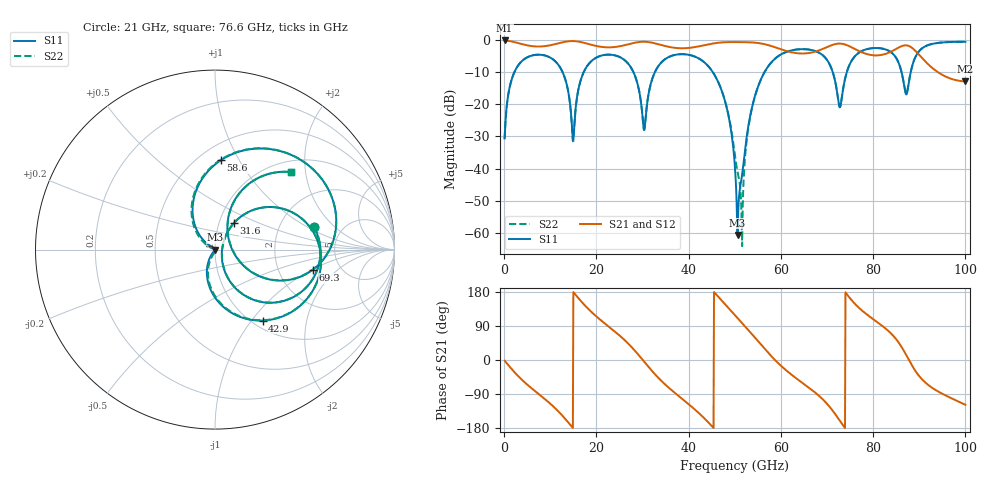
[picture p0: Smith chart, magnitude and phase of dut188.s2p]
! Touchstone file exported from HFSS 2026.1.0
!  File:  C:/ffzhzh/LocalFiles/Ansys_Project_Files/temp_test_TSV_RDL_188_1783478084_46308.aedt
!  Generated:  10:45:06 AM Jul  8, 2026
!  Design:  TSV_RDL
!  Project:  temp_test_TSV_RDL_188_1783478084_46308
! Variables:
!  h_bsmrdl = 2.62um
!  h_ox = 20um
!  h_rdl = 5um
!  h_sub = 55.96um
!  h_tmrdl = 3.07um
!  h_tsv = 55.96um
!  h_via = 3um
!  l_bsmrdl = 450.23um
!  l_sub = 4225.62um
!  l_tmrdl = 588.59um
!  m_sub = 200um
!  pitch = 55.14um
!  r_tsv = 11.97um
!  s_tmrdl = 10um
!  w_bsmrdl = 13.92um
!  w_sub = 500um
!  w_tmrdl = 26.27um
!  x_tsv_center1 = 601.725um
!  x_tsv_center2 = 1065.875um
!  x_tsv_center3 = 1680.735um
!  x_tsv_center4 = 2144.885um
!  x_tsv_center5 = 2759.745um
!  x_tsv_center6 = 3223.895um
# GHz S MA R 50.000000
! Terminal data exported
! Port[1] = TM_RDL1_1_T1
! Port[2] = TM_RDL5_1_T1
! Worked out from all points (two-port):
!   1000 points, 100 MHz to 100 GHz, reference 50 ohm
!   highest |S21| = -0.21 dB at 100 MHz (marker M1); lowest = -12.9 dB at 100 GHz (marker M2)
!   |S21| within 3 dB of the highest: start of sweep to 60.56 GHz; 68.43 GHz to 76.52 GHz (8.091 GHz wide, 11.2 % of centre) (the widest 2 of 3)
!   lowest |S11| = -60.6 dB at 50.6 GHz (marker M3), VSWR 1.00, Z = 50.1 - j0.0311 ohm
!   |S11| at or under -10 dB: 12.65 GHz to 17.27 GHz (4.615 GHz wide, 30.9 % of centre); 28.01 GHz to 32.7 GHz (4.686 GHz wide, 15.4 % of centre); 45.21 GHz to 56.47 GHz (11.26 GHz wide, 22.1 % of centre) (the widest 3 of 6)
!   |S22| runs from -64.1 to -0.6 dB; largest |S21 - S12| = 1.8e-14
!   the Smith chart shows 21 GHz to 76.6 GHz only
!   S11 on the Smith chart (normalised r, x): 21 GHz: 3.15, +1.15; 31.6 GHz: 1.18, +0.36; 42.9 GHz: 1.11, -1.14; 58.6 GHz: 0.63, +0.84; 69.3 GHz: 3.14, -1.02; 76.6 GHz: 1.22, +1.67
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0.1  0.02937 33.3  0.9758 -1.6  0.9758 -1.6  0.02937 33.3
! Gamma 0 0 0 0
! Port Impedance 50 0 50 0
2.8  0.377 46.3  0.8978 -39.5  0.8978 -39.5  0.377 46.2
9.4  0.5532 -19.6  0.8076 -109.0  0.8076 -109.0  0.5532 -19.7
14.9  0.02777 -15.5  0.9547 -179.3  0.9547 -179.3  0.02651 -16.3
16.8  0.2614 56.6  0.916 153.4  0.916 153.4  0.2612 56.9
21  0.5659 12.6  0.7769 104.6  0.7769 104.6  0.5658 12.8
31.6  0.1822 54.6  0.9141 -22.5  0.9141 -22.5  0.1825 54.4
33.4  0.3873 37.8  0.8536 -46.7  0.8536 -46.7  0.3874 37.8
42.9  0.4763 -56.1  0.8093 -148.0  0.8093 -148.0  0.4765 -55.6
47.8  0.117 -112.4  0.9152 148.4  0.9152 148.4  0.1184 -108.9
50.1  0.009014 -121.8  0.9209 117.3  0.9209 117.3  0.01489 -93.7
50.6  0.0009326 -19.4  0.9204 110.6  0.9204 110.6  0.008891 -64.3
51.5  0.007212 93.5  0.9191 98.5  0.9191 98.5  0.001425 -51.0
53.9  0.1 139.0  0.9078 65.6  0.9078 65.6  0.09781 143.7
58.6  0.4997 86.2  0.7701 1.4  0.7701 1.4  0.499 86.9
66.7  0.6914 12.2  0.6342 -78.8  0.6342 -78.8  0.6913 12.4
69.3  0.5561 -11.7  0.7321 -106.5  0.7321 -106.5  0.5561 -11.5
72.8  0.08927 20.5  0.8722 -160.5  0.8722 -160.5  0.09038 20.6
76.6  0.6051 45.6  0.6863 141.4  0.6863 141.4  0.6053 45.5
83.4  0.6733 -10.8  0.6311 75.6  0.6311 75.6  0.6737 -10.7
87.6  0.1879 42.0  0.8085 3.4  0.8085 3.4  0.1908 41.0
100  0.9302 -28.6  0.2258 -118.2  0.2258 -118.2  0.9302 -29.0
